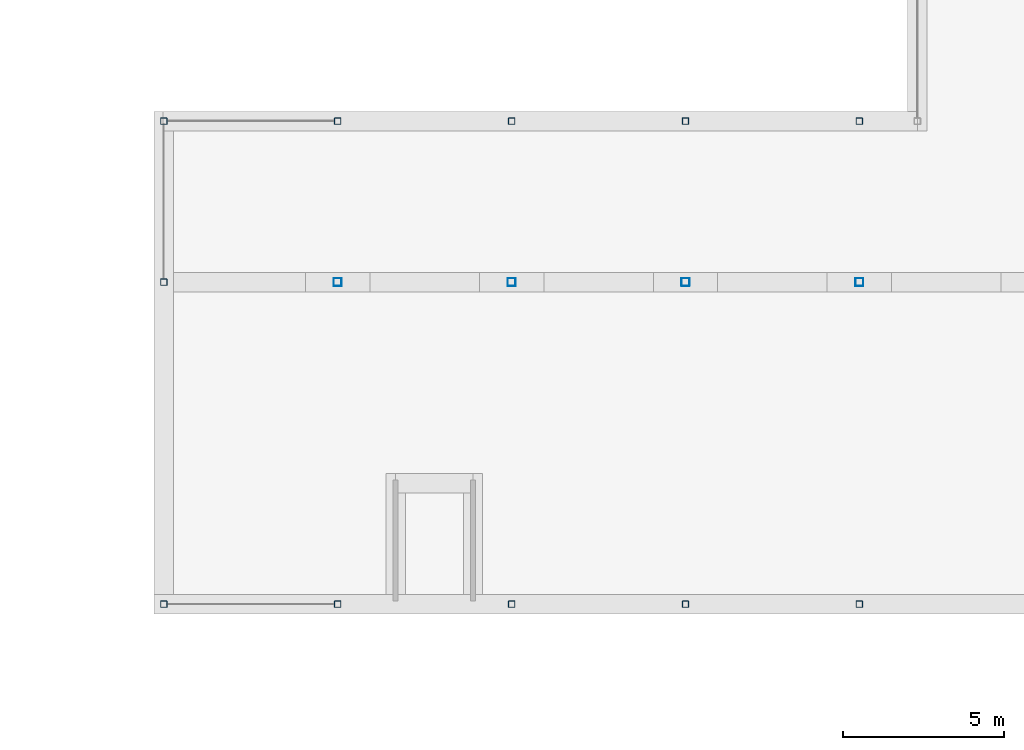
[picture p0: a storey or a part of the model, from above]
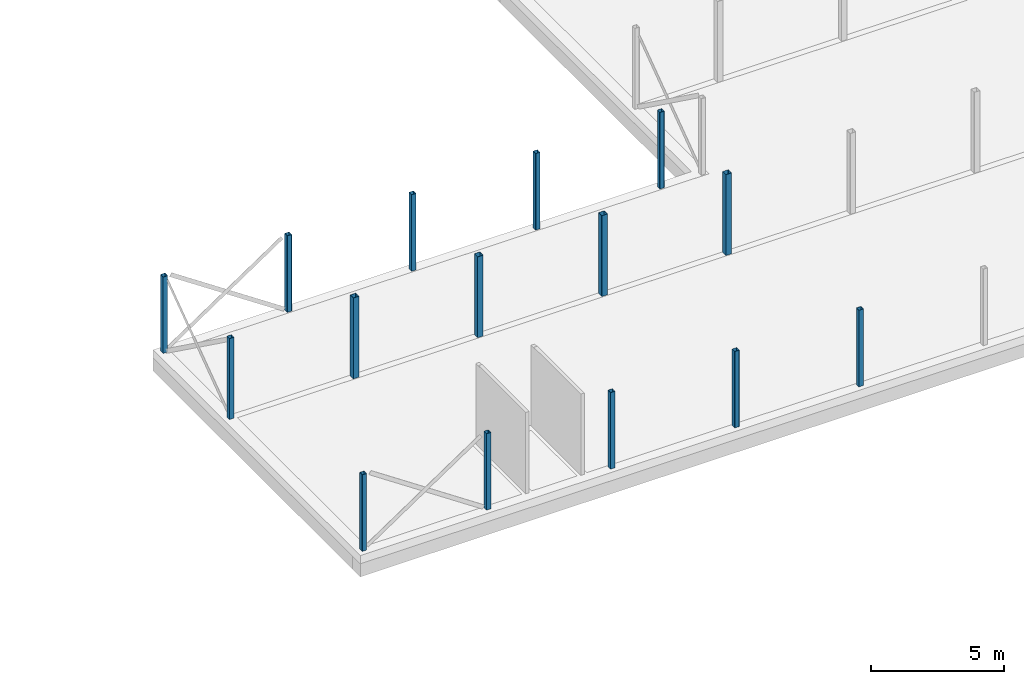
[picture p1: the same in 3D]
Properties of the parts of a building model (IFC2X3)

# File
Description: ViewDefinition [CoordinationView_V2.0], RevitIdentifiers [VersionGUID: df38b87c-a8f3-428a-bf3a-4e37a0c628fd, NumberOfSaves: 100], CoordinateReference [CoordinateBase: Project Base Point, ProjectSite: Internal]
File name: 11587
Time: 2025-03-17T10:09:42+01:00
Organization: Van Rossum Raadgevende Ingenieurs BV
Written by: ODA SDAI 24.6
Made in: Autodesk Revit 24.2.10.64 (ENU) - IFC 24.2.10.64

# IfcProject, 11587
LongName: Fokker hal 33; Phase: TO

# IfcSite, Default
RefLatitude: 42, 24, 53, 508911; RefLongitude: -71, -15, -29, -58837; RefElevation: 0 mm

# IfcBuilding
Pset_BuildingCommon - NumberOfStoreys: 12

# IfcBuildingStorey: Level:VRI_level (12)
Pset_AirSideSystemInformation - sets with these values: 2
Name | LongName = Name | Elevation (mm)
-1 kelder | -1 kelder | -3000
00 begane grond | 00 begane grond | 0
01 eerste verdieping | 01 eerste verdieping | 4000
02 tweede verdieping | 02 tweede verdieping | 7750
03 derde verdieping | 03 derde verdieping | 9000
04 vierde verdieping | 04 vierde verdieping | 12000
05 vijfde verdieping | 05 vijfde verdieping | 15000
06 zesde verdieping | 06 zesde verdieping | 18000
07 zevende verdieping | 07 zevende verdieping | 21000
08 achtste verdieping | 08 achtste verdieping | 24000
09 negende verdieping | 09 negende verdieping | 27000
10 tiende verdieping | 10 tiende verdieping | 30000

# IfcBeam: 16_SFR_VRI_balk_beton:600x1000, 16_SFR_VRI_balk_beton:600x1000:459432
In: 00 begane grond
Type - Pset_BeamCommon - IsExternal: no; LoadBearing: yes
Type - Pset_ReinforcementBarPitchOfBeam - Description: funderingsbalk
Classification: 16.12 Uniformat (Uniformat); Material: VRI_beton_ihwg
Pset_BeamCommon - Slope: 0 deg; Reference: 600x1000; Span: 16650 mm
Pset_QuantityTakeOff - Reference: 600x1000; sets with these values: 2

# IfcBeam: 16_SFR_VRI_balk_beton:600x1200 (6)
In: 00 begane grond
Type - Pset_BeamCommon - IsExternal: no; LoadBearing: yes
Type - Pset_ReinforcementBarPitchOfBeam - Description: funderingsbalk
Classification: 16.12 Uniformat (Uniformat); Material: VRI_beton_ihwg
Pset_BeamCommon - Slope: 0 deg; Reference: 600x1200
Pset_QuantityTakeOff - Reference: 600x1200; sets with these values: 2
Name (16_SFR_VRI_balk_beton:600x1200:...) | Span (mm)
459492 | 5275
459995 | 5275
460075 | 2400
501448 | 2375
652439 | 3900
652622 | 3875

# IfcBeam: 16_SFR_VRI_balk_beton:600x600 (2)
In: 00 begane grond
Type - PredefinedType: BEAM; Material: VRI_beton_ihwg
Type - Pset_BeamCommon - IsExternal: no; LoadBearing: yes
Type - Pset_ReinforcementBarPitchOfBeam - Description: funderingsbalk
Classification: 16.12 Uniformat (Uniformat)
Pset_BeamCommon - Reference: 600x600; Slope: 0 deg
Pset_QuantityTakeOff - Reference: 600x600; sets with these values: 2
Name (16_SFR_VRI_balk_beton:600x600:...) | Span (mm)
459368 | 42200
508597 | 18800

# IfcBeam: 16_SFR_VRI_balk_beton:600x600 (15)
In: 00 begane grond
Type - Pset_BeamCommon - IsExternal: no; LoadBearing: yes
Type - Pset_ReinforcementBarPitchOfBeam - Description: funderingsbalk
Classification: 16.12 Uniformat (Uniformat); Material: VRI_beton_ihwg
Pset_BeamCommon - Reference: 600x600; Slope: 0 deg
Pset_QuantityTakeOff - Reference: 600x600; sets with these values: 2
Name (16_SFR_VRI_balk_beton:600x600:...) | Span (mm)
459243 | 43200
459715 | 23420
459948 | 5425
474605 | 2400
475483 | 3753
483376 | 19800
483438 | 15000
512095 | 7925
518856 | 1780
519131 | 3753
595130 | 15000
654441 | 3050
654489 | 3977
654549 | 3977
654611 | 3050

# IfcBeam: 28_SFR_VRI_balk_staal_H:HEB180 (9)
In: 02 tweede verdieping
Type - Pset_BeamCommon - IsExternal: no; LoadBearing: yes
Type - Pset_ReinforcementBarPitchOfBeam - Description: HEB180
Classification: 28.11 Uniformat (Uniformat); Material: VRI_staal
Pset_BeamCommon - Slope: 0 deg; Reference: HEB180
Pset_QuantityTakeOff - Reference: HEB180; sets with these values: 2
Name (28_SFR_VRI_balk_staal_H:HEB180:...) | Span (mm)
469221 | 23400
469224 | 19800
469226 | 43200
469229 | 4575
469231 | 2075
469235 | 5000
469236 | 5000
475197 | 5425
591048 | 7925

# IfcBeam: 28_SFR_VRI_balk_staal_H:HEB200 (3)
In: 02 tweede verdieping
Type - Pset_BeamCommon - IsExternal: no; LoadBearing: yes
Type - Pset_ReinforcementBarPitchOfBeam - Description: HEB200
Classification: 28.11 Uniformat (Uniformat); Material: VRI_staal
Pset_BeamCommon - Slope: 0 deg; Reference: HEB200; Span: 10000 mm
Pset_QuantityTakeOff - Reference: HEB200; sets with these values: 2
Name (28_SFR_VRI_balk_staal_H:HEB200:...)
469230
469234
469237

# IfcBeam: 28_SFR_VRI_balk_staal_H:HEB220 (9)
In: 01 eerste verdieping
Type - Pset_BeamCommon - IsExternal: no; LoadBearing: yes
Type - Pset_ReinforcementBarPitchOfBeam - Description: HEB220
Classification: 28.11 Uniformat (Uniformat); Material: VRI_staal
Pset_BeamCommon - Slope: 0 deg; Reference: HEB220
Pset_QuantityTakeOff - Reference: HEB220; sets with these values: 2
Name (28_SFR_VRI_balk_staal_H:HEB220:...) | Span (mm)
461346 | 23400
462911 | 19800
464276 | 43200
465162 | 4575
466235 | 1950
466386 | 7950
466637 | 5425
466967 | 5000
467230 | 5000

# IfcBeam: 28_SFR_VRI_balk_staal_H:HEB240 (3)
In: 01 eerste verdieping
Type - Pset_BeamCommon - IsExternal: no; LoadBearing: yes
Type - Pset_ReinforcementBarPitchOfBeam - Description: HEB240
Classification: 28.11 Uniformat (Uniformat); Material: VRI_staal
Pset_BeamCommon - Slope: 0 deg; Reference: HEB240; Span: 10000 mm
Pset_QuantityTakeOff - Reference: HEB240; sets with these values: 2
Name (28_SFR_VRI_balk_staal_H:HEB240:...)
465955
466805
467403

# IfcBeam: 28_SFR_VRI_balk_staal_SFB_eenzijdiig:HEB180_340x15 (2)
In: 02 tweede verdieping
Type - PredefinedType: BEAM; Material: VRI_staal
Type - Pset_BeamCommon - IsExternal: no; LoadBearing: yes
Type - Pset_ReinforcementBarPitchOfBeam - Description: SFB-ligger HEB180 340x15
Classification: 28.11 Uniformat (Uniformat)
Pset_BeamCommon - Slope: 0 deg; Reference: HEB180_340x15; Span: 5275 mm
Pset_QuantityTakeOff - Reference: HEB180_340x15; sets with these values: 2
Name (28_SFR_VRI_balk_staal_SFB_eenzijdiig:HEB180_340x15:...)
469227
469228

# IfcBeam: 28_SFR_VRI_balk_staal_SFB_eenzijdiig:HEB220_340x15 (2)
In: 01 eerste verdieping
Type - PredefinedType: BEAM; Material: VRI_staal
Type - Pset_BeamCommon - IsExternal: no; LoadBearing: yes
Type - Pset_ReinforcementBarPitchOfBeam - Description: SFB-ligger HEB220 340x15
Classification: 28.11 Uniformat (Uniformat)
Pset_BeamCommon - Slope: 0 deg; Reference: HEB220_340x15; Span: 5275 mm
Pset_QuantityTakeOff - Reference: HEB220_340x15; sets with these values: 2
Name (28_SFR_VRI_balk_staal_SFB_eenzijdiig:HEB220_340x15:...)
464398
465118

# IfcBeam: 28_SFR_VRI_balk_staal_THQ:THQ200x5-190x15-400x15, 28_SFR_VRI_balk_staal_THQ:THQ200x5-190x15-400x15:469225
In: 02 tweede verdieping
Type - Pset_BeamCommon - IsExternal: no; LoadBearing: yes
Type - Pset_ReinforcementBarPitchOfBeam - Description: THQ200x5-190x15-400x15
Classification: 28.11 Uniformat (Uniformat); Material: VRI_staal
Pset_BeamCommon - Slope: 0 deg; Reference: THQ200x5-190x15-400x15; Span: 48475 mm
Pset_QuantityTakeOff - Reference: THQ200x5-190x15-400x15; sets with these values: 2

# IfcBeam: 28_SFR_VRI_balk_staal_THQ:THQ200x8-190x20-400x20, 28_SFR_VRI_balk_staal_THQ:THQ200x8-190x20-400x20:469223
In: 02 tweede verdieping
Type - Pset_BeamCommon - IsExternal: no; LoadBearing: yes
Type - Pset_ReinforcementBarPitchOfBeam - Description: THQ200x8-190x20-400x20
Classification: 28.11 Uniformat (Uniformat); Material: VRI_staal
Pset_BeamCommon - Slope: 0 deg; Reference: THQ200x8-190x20-400x20; Span: 25075 mm
Pset_QuantityTakeOff - Reference: THQ200x8-190x20-400x20; sets with these values: 2

# IfcBeam: 28_SFR_VRI_balk_staal_THQ:THQ265x6-190x20-400x20, 28_SFR_VRI_balk_staal_THQ:THQ265x6-190x20-400x20:462351
In: 01 eerste verdieping
Type - Pset_BeamCommon - IsExternal: no; LoadBearing: yes
Type - Pset_ReinforcementBarPitchOfBeam - Description: THQ265x6-190x20-400x20
Classification: 28.11 Uniformat (Uniformat); Material: VRI_staal
Pset_BeamCommon - Slope: 0 deg; Reference: THQ265x6-190x20-400x20; Span: 23400 mm
Pset_QuantityTakeOff - Reference: THQ265x6-190x20-400x20; sets with these values: 2

# IfcBeam: 28_SFR_VRI_balk_staal_THQ:THQ265x8-190x20-400x20 (4)
In: 01 eerste verdieping
Type - Pset_BeamCommon - IsExternal: no; LoadBearing: yes
Type - Pset_ReinforcementBarPitchOfBeam - Description: THQ265x8-190x20-400x20
Classification: 28.11 Uniformat (Uniformat); Material: VRI_staal
Pset_BeamCommon - Slope: 0 deg; Reference: THQ265x8-190x20-400x20
Pset_QuantityTakeOff - Reference: THQ265x8-190x20-400x20; sets with these values: 2
Name (28_SFR_VRI_balk_staal_THQ:THQ265x8-190x20-400x20:...) | Span (mm)
462542 | 25075
463413 | 25075
468718 | 3050
468899 | 2475

# IfcBeam: 28_SFR_VRI_balk_staal_strip:10x180 (24)
Type - Pset_BeamCommon - IsExternal: no; LoadBearing: yes
Type - Pset_ReinforcementBarPitchOfBeam - Description: ≠180x10
Classification: 28.11 Uniformat (Uniformat); Material: VRI_staal
Pset_BeamCommon - Reference: 10x180
Pset_QuantityTakeOff - Reference: 10x180; sets with these values: 2
Name (28_SFR_VRI_balk_staal_strip:10x180:...) | In | Span (mm) | Slope (deg)
479749 | 00 begane grond | 6174.81 | 35.8343
480353 | 01 eerste verdieping | 6347.29 | 38.0254
480718 | 00 begane grond | 6170.76 | 35.8615
480719 | 01 eerste verdieping | 6347.29 | 38.0254
481203 | 01 eerste verdieping | 6666.94 | 35.9073
481284 | 00 begane grond | 6504.66 | 33.8688
481805 | 01 eerste verdieping | 6666.94 | 35.9073
481806 | 00 begane grond | 6503.89 | 33.8733
483851 | 00 begane grond | 10631.2 | 19.9206
483852 | 01 eerste verdieping | 10584.9 | 21.3555
483853 | 00 begane grond | 10629.6 | 19.9237
483854 | 01 eerste verdieping | 10584.9 | 21.3555
593624 | 01 eerste verdieping | 6666.94 | 35.9073
593625 | 00 begane grond | 6503.89 | 33.8733
593626 | 01 eerste verdieping | 6666.94 | 35.9073
593627 | 00 begane grond | 6504.66 | 33.8688
595811 | 00 begane grond | 6169.95 | 35.8669
595812 | 01 eerste verdieping | 6347.29 | 38.0254
595813 | 00 begane grond | 6170.76 | 35.8615
595814 | 01 eerste verdieping | 6347.29 | 38.0254
596109 | 01 eerste verdieping | 6666.94 | 35.9073
596110 | 00 begane grond | 6504.66 | 33.8688
596111 | 01 eerste verdieping | 6666.94 | 35.9073
596112 | 00 begane grond | 6503.89 | 33.8733

# IfcBeam: 28_SFR_VRI_balk_staal_strip:160x5 (4)
Type - Pset_BeamCommon - IsExternal: no; LoadBearing: yes
Type - Pset_ReinforcementBarPitchOfBeam - Description: ≠160x5
Classification: 28.11 Uniformat (Uniformat); Material: VRI_staal
Pset_BeamCommon - Slope: 0 deg; Reference: 160x5; Span: 28500 mm
Pset_QuantityTakeOff - Reference: 160x5; sets with these values: 2
Name (28_SFR_VRI_balk_staal_strip:160x5:...) | In
636362 | 01 eerste verdieping
637030 | 01 eerste verdieping
637519 | 02 tweede verdieping
637520 | 02 tweede verdieping

# IfcBuildingElementProxy: 000_00_VRI_nulpunt_1:000_00_VRI_nulpunt_1, 000_00_VRI_nulpunt_1:000_00_VRI_nulpunt_1:233295
In: 00 begane grond
Type - Material: VRI_tekst, VRI_nulpunt
Pset_BuildingElementProxyCommon - Reference: 000_00_VRI_nulpunt_1; sets with these values: 2

# IfcBuildingElementProxy: 000_00_VRI_nulpunt_2:000_00_VRI_nulpunt_2, 000_00_VRI_nulpunt_2:000_00_VRI_nulpunt_2:278477
In: 00 begane grond
Type - Material: VRI_nulpunt
Type - Pset_ManufacturerTypeInformation - Manufacturer: Van Rossum
Pset_BuildingElementProxyCommon - Reference: 000_00_VRI_nulpunt_2; sets with these values: 2

# IfcColumn: 28_SC_VRI_kolom_staal_betongevuld_koker:K250x250x8_gevuld (8)
Type - PredefinedType: COLUMN; Material: VRI_beton_ihwg, VRI_staal
Type - Pset_ColumnCommon - IsExternal: no; LoadBearing: yes
Type - Pset_ReinforcementBarPitchOfColumn - Description: K250x250x8 betongevuld met wapening
Classification: 28.11 Uniformat (Uniformat)
Pset_ColumnCommon - Reference: K250x250x8_gevuld
Pset_QuantityTakeOff - Reference: K250x250x8_gevuld; sets with these values: 2
Name (28_SC_VRI_kolom_staal_betongevuld_koker:K250x250x8_gevuld:...) | In
457235 | 00 begane grond
457339 | 00 begane grond
458086 | 00 begane grond
458136 | 00 begane grond
471275 | 01 eerste verdieping
471276 | 01 eerste verdieping
471296 | 01 eerste verdieping
471297 | 01 eerste verdieping

# IfcColumn: 28_SC_VRI_kolom_staal_koker:K200x200x8 (48)
Type - PredefinedType: COLUMN; Material: VRI_staal
Type - Pset_ColumnCommon - IsExternal: no; LoadBearing: yes
Type - Pset_ReinforcementBarPitchOfColumn - Description: K200x200x8
Classification: 28.11 Uniformat (Uniformat)
Pset_ColumnCommon - Reference: K200x200x8
Pset_QuantityTakeOff - Reference: K200x200x8; sets with these values: 2
Name (28_SC_VRI_kolom_staal_koker:K200x200x8:...) | In
455254 | 00 begane grond
455351 | 00 begane grond
456407 | 00 begane grond
456523 | 00 begane grond
456533 | 00 begane grond
456545 | 00 begane grond
457018 | 00 begane grond
457095 | 00 begane grond
457120 | 00 begane grond
457569 | 00 begane grond
457650 | 00 begane grond
457699 | 00 begane grond
457741 | 00 begane grond
457801 | 00 begane grond
457882 | 00 begane grond
457927 | 00 begane grond
457937 | 00 begane grond
457975 | 00 begane grond
457985 | 00 begane grond
457995 | 00 begane grond
458026 | 00 begane grond
471264 | 01 eerste verdieping
471265 | 01 eerste verdieping
471266 | 01 eerste verdieping
471267 | 01 eerste verdieping
471268 | 01 eerste verdieping
471269 | 01 eerste verdieping
471271 | 01 eerste verdieping
471273 | 01 eerste verdieping
471274 | 01 eerste verdieping
471284 | 01 eerste verdieping
471285 | 01 eerste verdieping
471286 | 01 eerste verdieping
471287 | 01 eerste verdieping
471288 | 01 eerste verdieping
471289 | 01 eerste verdieping
471290 | 01 eerste verdieping
471291 | 01 eerste verdieping
471292 | 01 eerste verdieping
471293 | 01 eerste verdieping
471294 | 01 eerste verdieping
471295 | 01 eerste verdieping
587969 | 00 begane grond
588005 | 01 eerste verdieping
588022 | 00 begane grond
588024 | 00 begane grond
588026 | 01 eerste verdieping
588028 | 01 eerste verdieping

# IfcColumn: 28_SC_VRI_kolom_staal_koker:K250x250x8 (24)
Type - PredefinedType: COLUMN; Material: VRI_staal
Type - Pset_ColumnCommon - IsExternal: no; LoadBearing: yes
Type - Pset_ReinforcementBarPitchOfColumn - Description: K250x250x8
Classification: 28.11 Uniformat (Uniformat)
Pset_ColumnCommon - Reference: K250x250x8
Pset_QuantityTakeOff - Reference: K250x250x8; sets with these values: 2
Name (28_SC_VRI_kolom_staal_koker:K250x250x8:...) | In
457390 | 00 begane grond
457489 | 00 begane grond
457503 | 00 begane grond
457531 | 00 begane grond
457547 | 00 begane grond
457557 | 00 begane grond
458229 | 00 begane grond
458285 | 00 begane grond
471277 | 01 eerste verdieping
471278 | 01 eerste verdieping
471279 | 01 eerste verdieping
471280 | 01 eerste verdieping
471281 | 01 eerste verdieping
471282 | 01 eerste verdieping
471283 | 01 eerste verdieping
471299 | 01 eerste verdieping
471300 | 01 eerste verdieping
517189 | 00 begane grond
517340 | 01 eerste verdieping
587922 | 00 begane grond
588023 | 00 begane grond
588025 | 00 begane grond
588027 | 01 eerste verdieping
588029 | 01 eerste verdieping

# IfcOpeningElement: Opening (179)
Name | In
12 x Floor:23_FL_VRI_geïsoleerde_kanaalplaatvloer_260_Rc=....:452974 | 00 begane grond | Classification: 23.21 Uniformat (Uniformat); Pset_OpeningElementCommon - Reference: K250x250x8; sets with these values: 2
2 x Floor:23_FL_VRI_geïsoleerde_kanaalplaatvloer_260_Rc=....:452954 | 00 begane grond | Classification: 23.21 Uniformat (Uniformat); Pset_OpeningElementCommon - Reference: 23_FL_VRI_geïsoleerde_kanaalplaatvloer_260_Rc=....; sets with these values: 2
4 x Floor:23_FL_VRI_kanaalplaatvloer_260:460249 | 01 eerste verdieping | Classification: 23.21 Uniformat (Uniformat); Pset_OpeningElementCommon - Reference: THQ265x8-190x20-400x20; sets with these values: 2
Floor:23_FL_VRI_kanaalplaatvloer_260:460249 | 01 eerste verdieping | Classification: 23.21 Uniformat (Uniformat); Pset_OpeningElementCommon - Reference: THQ265x6-190x20-400x20; sets with these values: 2
20 x Floor:23_FL_VRI_kanaalplaatvloer_260:460249 | 01 eerste verdieping | Classification: 23.21 Uniformat (Uniformat); Pset_OpeningElementCommon - Reference: K200x200x8; sets with these values: 2
8 x Floor:23_FL_VRI_kanaalplaatvloer_260:460249 | 01 eerste verdieping | Classification: 23.21 Uniformat (Uniformat); Pset_OpeningElementCommon - Reference: 10x180; sets with these values: 2
3 x Floor:23_FL_VRI_kanaalplaatvloer_260:463597 | 01 eerste verdieping | Classification: 23.21 Uniformat (Uniformat); Pset_OpeningElementCommon - Reference: 23_FL_VRI_kanaalplaatvloer_260; sets with these values: 2
Basic Wall:22_WA_VRI_wand_kalkzandsteen_150:501806 | 00 begane grond | Classification: 22.21 Uniformat (Uniformat); Pset_OpeningElementCommon - Reference: THQ265x8-190x20-400x20; sets with these values: 2
Basic Wall:22_WA_VRI_wand_kalkzandsteen_150:502260 | 00 begane grond | Classification: 22.21 Uniformat (Uniformat); Pset_OpeningElementCommon - Reference: THQ265x8-190x20-400x20; sets with these values: 2
Basic Wall:22_WA_VRI_wand_kalkzandsteen_150:519462 | 00 begane grond | Classification: 22.21 Uniformat (Uniformat); Pset_OpeningElementCommon - Reference: THQ265x8-190x20-400x20; sets with these values: 2
Basic Wall:22_WA_VRI_wand_kalkzandsteen_150:520501 | 00 begane grond | Classification: 22.21 Uniformat (Uniformat); Pset_OpeningElementCommon - Reference: THQ265x8-190x20-400x20; sets with these values: 2
120 x  | 00 begane grond
2 x Floor:23_FL_VRI_betonvloer_380:639239:2 | 00 begane grond | Classification: 23.21 Uniformat (Uniformat); Pset_OpeningElementCommon - Reference: 23_FL_VRI_betonvloer_380; sets with these values: 2
Floor:23_FL_VRI_betonvloer_380:639239:3 | 00 begane grond | Classification: 23.21 Uniformat (Uniformat); Pset_OpeningElementCommon - Reference: 23_FL_VRI_betonvloer_380; sets with these values: 2
Floor:23_FL_VRI_betonvloer_380:639239:4 | 00 begane grond | Classification: 23.21 Uniformat (Uniformat); Pset_OpeningElementCommon - Reference: 23_FL_VRI_betonvloer_380; sets with these values: 2
Floor:23_FL_VRI_betonvloer_380:639239:5 | 00 begane grond | Classification: 23.21 Uniformat (Uniformat); Pset_OpeningElementCommon - Reference: 23_FL_VRI_betonvloer_380; sets with these values: 2

# IfcSlab: 16_SFO_VRI_beton_poer:600x1000x2000 (10)
In: 00 begane grond
Type - PredefinedType: BASESLAB; Material: VRI_beton_ihwg
Type - Pset_ReinforcementBarPitchOfSlab - Description: poer
Type - Pset_SlabCommon - IsExternal: no; LoadBearing: yes
Classification: 16.13 Uniformat (Uniformat)
Pset_QuantityTakeOff - Reference: 600x1000x2000; sets with these values: 2
Pset_SlabCommon - Reference: 600x1000x2000
Name (16_SFO_VRI_beton_poer:600x1000x2000:...) | PitchAngle (deg)
474290 | 0
474469 | 0
474477 | 0
474487 | 0
474495 | 0
474507 | 0
474570
474571
588513
588646

# IfcSlab: 16_SFO_VRI_beton_poer:600x1200x2000 (2)
In: 00 begane grond
Type - PredefinedType: BASESLAB; Material: VRI_beton_ihwg
Type - Pset_ReinforcementBarPitchOfSlab - Description: poer
Type - Pset_SlabCommon - IsExternal: no; LoadBearing: yes
Classification: 16.13 Uniformat (Uniformat)
Pset_QuantityTakeOff - Reference: 600x1200x2000; sets with these values: 2
Pset_SlabCommon - PitchAngle: 0 deg; Reference: 600x1200x2000
Name (16_SFO_VRI_beton_poer:600x1200x2000:...)
649494
649704

# IfcSlab: Floor:23_FL_VRI_betonvloer_260 (2)
Type - PredefinedType: FLOOR; Material: VRI_beton_ihwg 260 mm
Type - Pset_ReinforcementBarPitchOfSlab - Description: betonvloer
Type - Pset_SlabCommon - IsExternal: no
Classification: 23.21 Uniformat (Uniformat)
Pset_QuantityTakeOff - Reference: 23_FL_VRI_betonvloer_260; sets with these values: 2
Pset_SlabCommon - LoadBearing: yes; PitchAngle: 0 deg; Reference: 23_FL_VRI_betonvloer_260
Name (Floor:23_FL_VRI_betonvloer_260:...) | In
501306 | 01 eerste verdieping
509600 | 02 tweede verdieping

# IfcSlab: Floor:23_FL_VRI_betonvloer_380 (3)
In: 00 begane grond
Type - PredefinedType: FLOOR; Material: VRI_beton_ihwg 380 mm
Type - Pset_ReinforcementBarPitchOfSlab - Description: betonvloer
Type - Pset_SlabCommon - IsExternal: no
Classification: 23.21 Uniformat (Uniformat)
Pset_QuantityTakeOff - Reference: 23_FL_VRI_betonvloer_380; sets with these values: 2
Pset_SlabCommon - LoadBearing: yes; PitchAngle: 0 deg; Reference: 23_FL_VRI_betonvloer_380
Name (Floor:23_FL_VRI_betonvloer_380:...)
639239
639239:2
639239:3

# IfcSlab: Floor:23_FL_VRI_geïsoleerde_kanaalplaatvloer_260_Rc=...., Floor:23_FL_VRI_geïsoleerde_kanaalplaatvloer_260_Rc=....:452974
In: 00 begane grond
Type - PredefinedType: FLOOR; Material: VRI_beton_kanaalplaat 260 mm, VRI_isolatie 120 mm
Type - Pset_ReinforcementBarPitchOfSlab - Description: geïsoleerde kanaalplaatvloer
Type - Pset_SlabCommon - IsExternal: no
Classification: 23.21 Uniformat (Uniformat)
Pset_QuantityTakeOff - Reference: 23_FL_VRI_geïsoleerde_kanaalplaatvloer_260_Rc=....; sets with these values: 2
Pset_SlabCommon - Reference: 23_FL_VRI_geïsoleerde_kanaalplaatvloer_260_Rc=....; LoadBearing: yes; PitchAngle: 0 deg

# IfcSlab: Floor:23_FL_VRI_kanaalplaatvloer_200 (3)
In: 02 tweede verdieping
Type - PredefinedType: FLOOR; Material: VRI_beton_kanaalplaat 200 mm
Type - Pset_ReinforcementBarPitchOfSlab - Description: kanaalplaatvloer
Type - Pset_SlabCommon - IsExternal: no
Classification: 23.21 Uniformat (Uniformat)
Pset_QuantityTakeOff - Reference: 23_FL_VRI_kanaalplaatvloer_200; sets with these values: 2
Pset_SlabCommon - LoadBearing: yes; PitchAngle: 0 deg; Reference: 23_FL_VRI_kanaalplaatvloer_200
Name (Floor:23_FL_VRI_kanaalplaatvloer_200:...)
469209
469209:2
469209:3

# IfcSlab: Floor:23_FL_VRI_kanaalplaatvloer_260, Floor:23_FL_VRI_kanaalplaatvloer_260:460249
In: 01 eerste verdieping
Type - PredefinedType: FLOOR
Type - Pset_ReinforcementBarPitchOfSlab - Description: kanaalplaatvloer
Type - Pset_SlabCommon - IsExternal: no
Classification: 23.21 Uniformat (Uniformat); Material: VRI_beton_kanaalplaat
Pset_QuantityTakeOff - Reference: 23_FL_VRI_kanaalplaatvloer_260; sets with these values: 2
Pset_SlabCommon - LoadBearing: yes; PitchAngle: 0 deg; Reference: 23_FL_VRI_kanaalplaatvloer_260

# IfcWallStandardCase: Basic Wall:22_WA_VRI_wand_kalkzandsteen_150 (6)
In: 00 begane grond
Type - PredefinedType: STANDARD; Material: VRI_kalkzandsteen 150 mm
Type - Pset_ReinforcementBarPitchOfWall - Description: kalkzandsteen
Type - Pset_WallCommon - IsExternal: no
Classification: 22.21 Uniformat (Uniformat)
Pset_QuantityTakeOff - Reference: 22_WA_VRI_wand_kalkzandsteen_150; sets with these values: 2
Pset_WallCommon - LoadBearing: yes; Reference: 22_WA_VRI_wand_kalkzandsteen_150; ExtendToStructure: no
Name (Basic Wall:22_WA_VRI_wand_kalkzandsteen_150:...)
501806
502038
502260
502718
519462
520501
